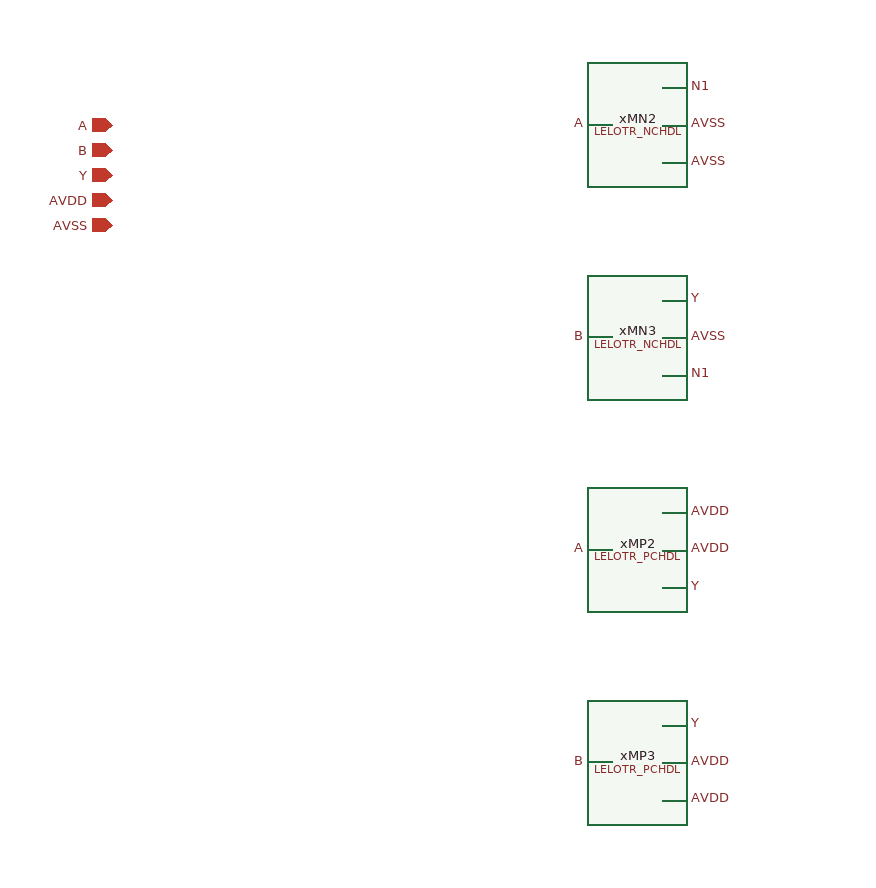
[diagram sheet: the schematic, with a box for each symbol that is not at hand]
v {xschem version=3.4.6 file_version=1.2}
G {}
K {}
V {}
S {}
E {}
N 620 -700 640 -700 {lab=N1}
N 560 -670 580 -670 {lab=A}
N 620 -640 640 -640 {lab=AVSS}
N 620 -670 640 -670 {lab=AVSS}
N 620 -530 640 -530 {lab=Y}
N 560 -500 580 -500 {lab=B}
N 620 -470 640 -470 {lab=N1}
N 620 -500 640 -500 {lab=AVSS}
N 620 -300 640 -300 {lab=Y}
N 560 -330 580 -330 {lab=A}
N 620 -360 640 -360 {lab=AVDD}
N 620 -330 640 -330 {lab=AVDD}
N 620 -130 640 -130 {lab=AVDD}
N 560 -160 580 -160 {lab=B}
N 620 -190 640 -190 {lab=Y}
N 620 -160 640 -160 {lab=AVDD}
C {devices/iopin.sym} 180 -670 0 0 {name=p5 lab=A}
C {devices/iopin.sym} 180 -650 0 0 {name=p6 lab=B}
C {devices/iopin.sym} 180 -630 0 0 {name=p7 lab=Y}
C {devices/iopin.sym} 180 -610 0 0 {name=p8 lab=AVDD}
C {devices/iopin.sym} 180 -590 0 0 {name=p9 lab=AVSS}
C {LELO_TR_IHP13G2/LELOTR_NCHDL.sym} 580 -670 0 0 {name=xMN2}
C {devices/lab_pin.sym} 640 -700 2 0 {name=l16 sig_type=std_logic lab=N1 }
C {devices/lab_pin.sym} 560 -670 0 0 {name=l17 sig_type=std_logic lab=A }
C {devices/lab_pin.sym} 640 -640 2 0 {name=l18 sig_type=std_logic lab=AVSS }
C {devices/lab_pin.sym} 640 -670 2 0 {name=l19 sig_type=std_logic lab=AVSS }
C {LELO_TR_IHP13G2/LELOTR_NCHDL.sym} 580 -500 0 0 {name=xMN3}
C {devices/lab_pin.sym} 640 -530 2 0 {name=l20 sig_type=std_logic lab=Y }
C {devices/lab_pin.sym} 560 -500 0 0 {name=l21 sig_type=std_logic lab=B }
C {devices/lab_pin.sym} 640 -470 2 0 {name=l22 sig_type=std_logic lab=N1 }
C {devices/lab_pin.sym} 640 -500 2 0 {name=l23 sig_type=std_logic lab=AVSS }
C {LELO_TR_IHP13G2/LELOTR_PCHDL.sym} 580 -330 0 0 {name=xMP2}
C {devices/lab_pin.sym} 640 -300 2 0 {name=l24 sig_type=std_logic lab=Y }
C {devices/lab_pin.sym} 560 -330 0 0 {name=l25 sig_type=std_logic lab=A }
C {devices/lab_pin.sym} 640 -360 2 0 {name=l26 sig_type=std_logic lab=AVDD }
C {devices/lab_pin.sym} 640 -330 2 0 {name=l27 sig_type=std_logic lab=AVDD }
C {LELO_TR_IHP13G2/LELOTR_PCHDL.sym} 580 -160 0 0 {name=xMP3}
C {devices/lab_pin.sym} 640 -130 2 0 {name=l28 sig_type=std_logic lab=AVDD }
C {devices/lab_pin.sym} 560 -160 0 0 {name=l29 sig_type=std_logic lab=B }
C {devices/lab_pin.sym} 640 -190 2 0 {name=l30 sig_type=std_logic lab=Y }
C {devices/lab_pin.sym} 640 -160 2 0 {name=l31 sig_type=std_logic lab=AVDD }
